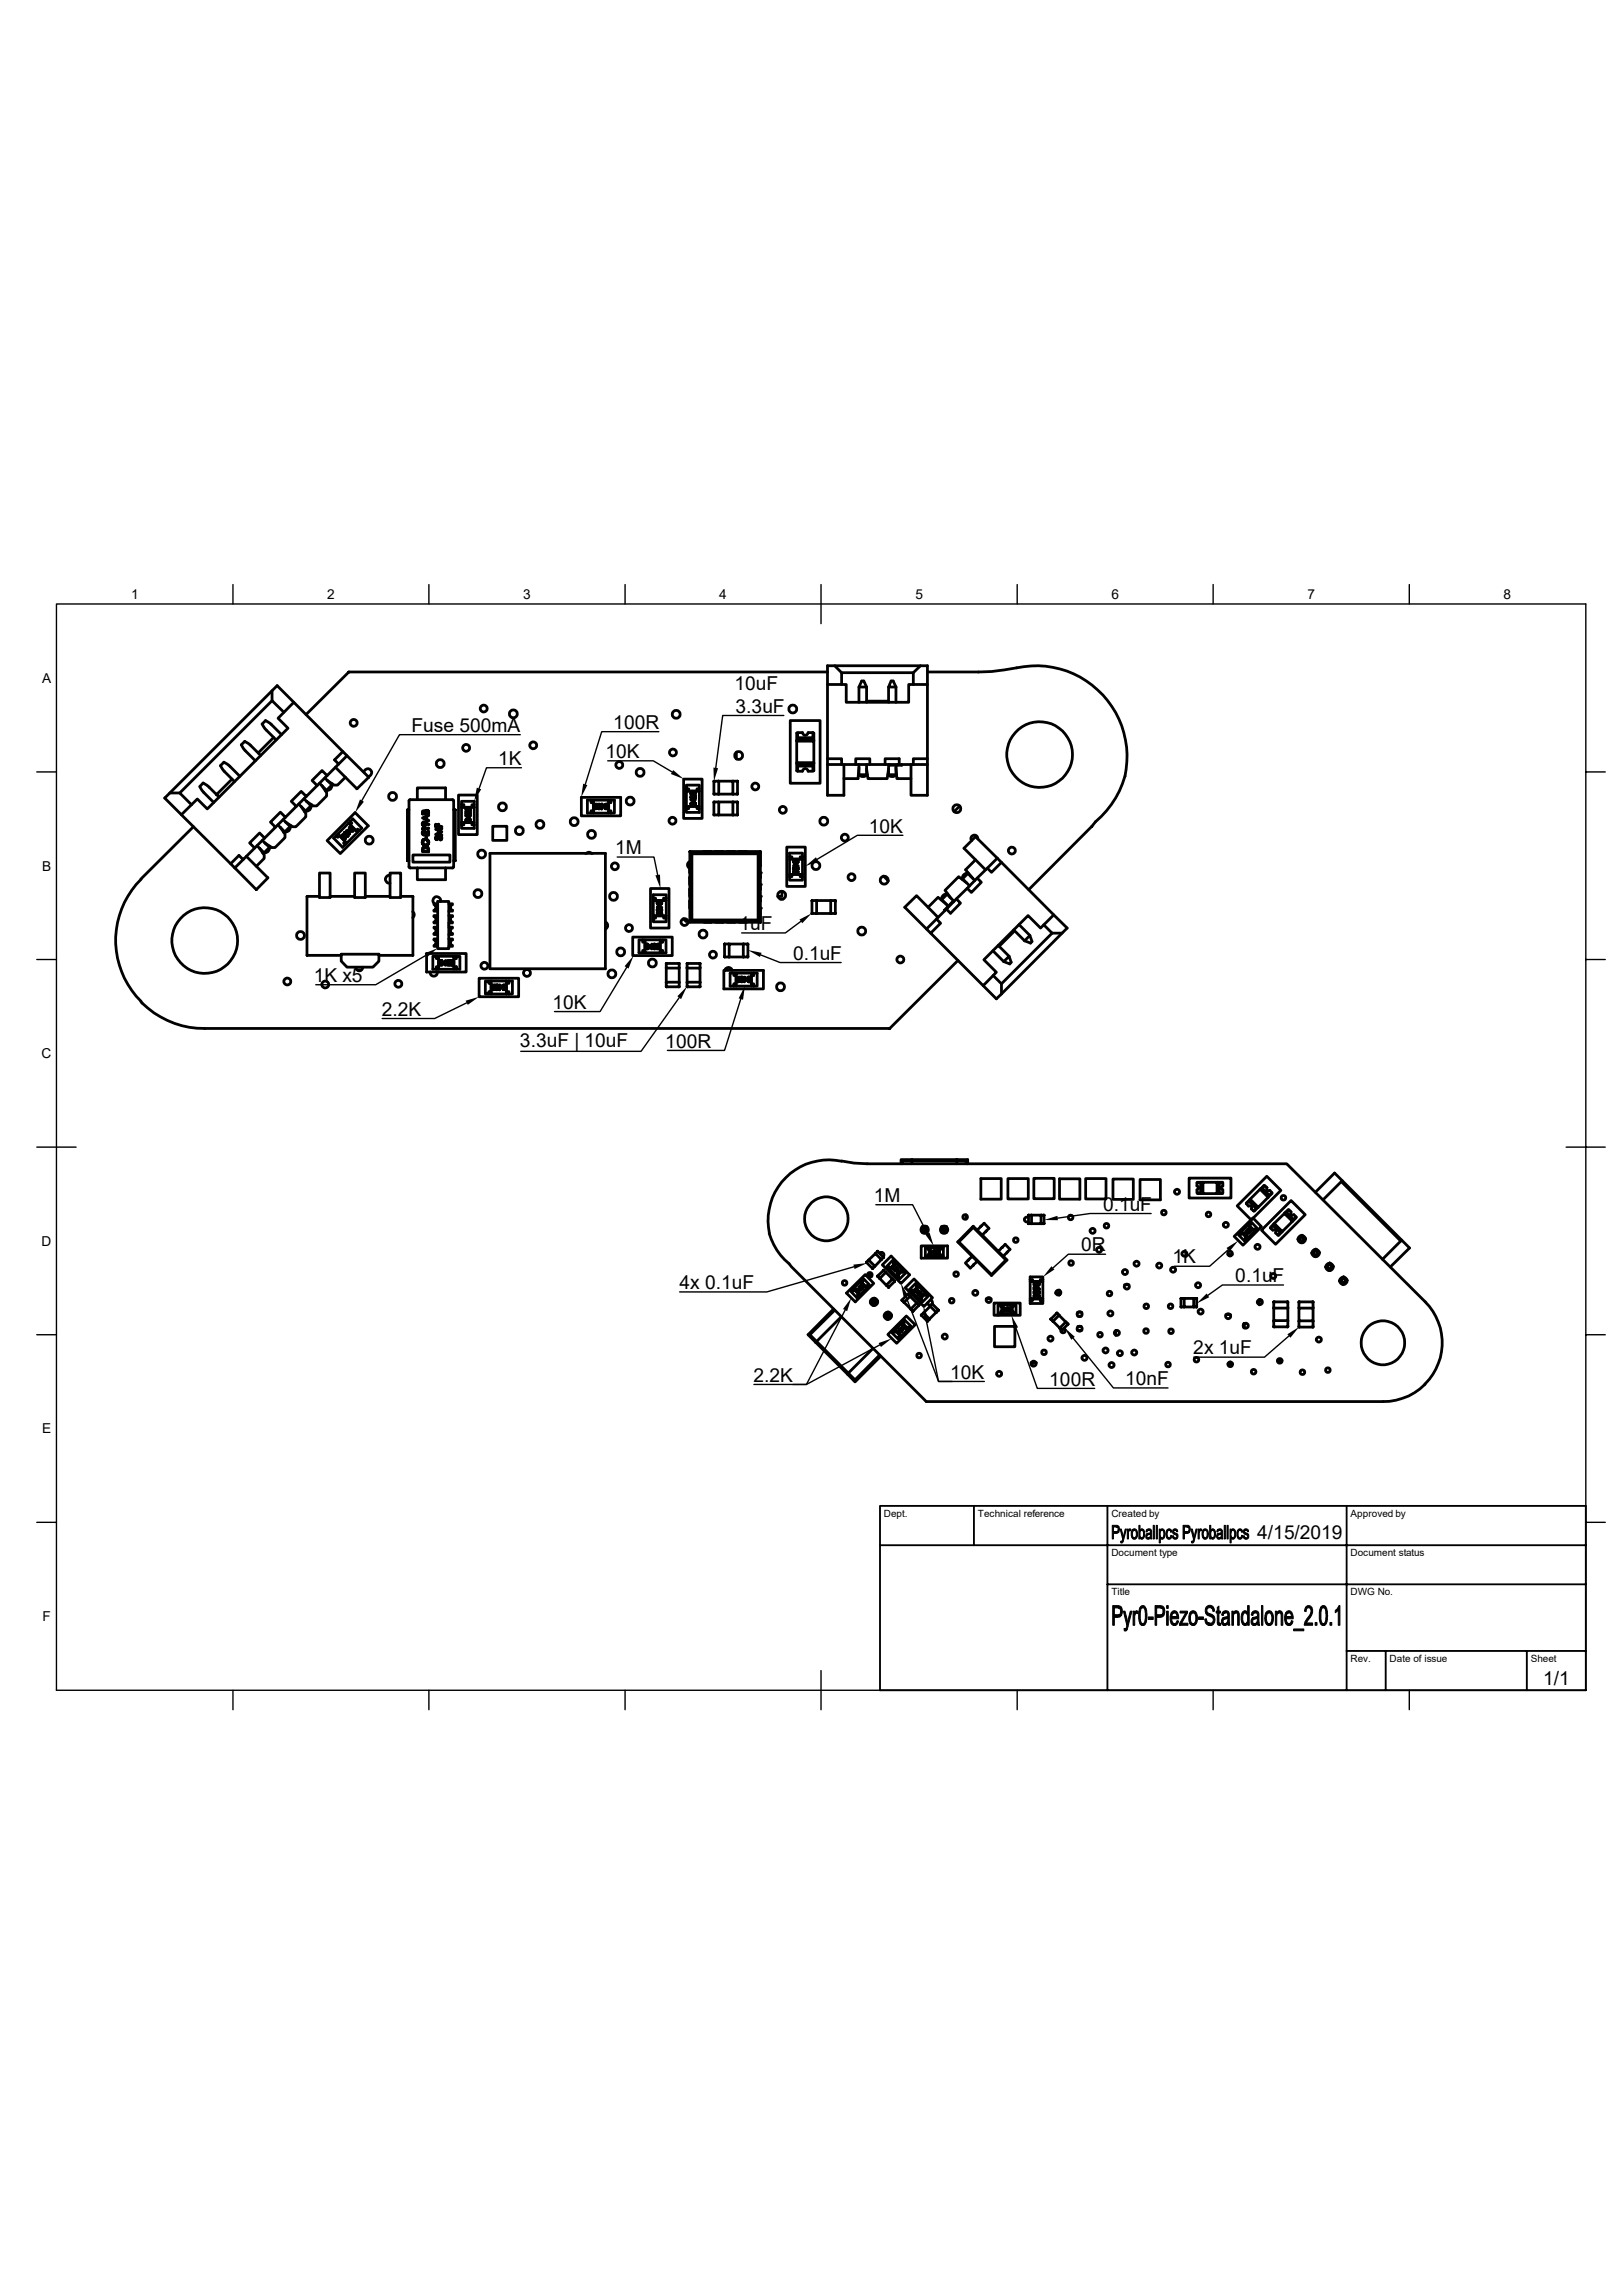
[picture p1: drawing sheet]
<svg xmlns="http://www.w3.org/2000/svg" width="297mm" height="420mm" viewBox="0 0 297 420" stroke-linecap="round" stroke-linejoin="round" font-family="sans-serif">
<defs><g id="words">
<g font-size="3.5">
<text x="134.4" y="126.2">10uF</text>
<text x="134.6" y="130.4">3.3uF</text>
<text x="75.3" y="133.9">Fuse 500mA</text>
<text x="112.2" y="133.4">100R</text>
<text x="91.1" y="140">1K</text>
<text x="110.8" y="138.8">10K</text>
<text x="159" y="152.4">10K</text>
<text x="112.6" y="156.3">1M</text>
<text x="135.3" y="170.2">1uF</text>
<text x="57.4" y="179.7">1K x5</text>
<text x="145.1" y="175.6">0.1uF</text>
<text x="69.9" y="185.9">2.2K</text>
<text x="101.1" y="184.7">10K</text>
<text x="95.1" y="191.6">3.3uF | 10uF</text>
<text x="121.8" y="191.7">100R</text>
<text x="159.9" y="220">1M</text>
<text x="201.8" y="221.6">0.1uF</text>
<text x="197.9" y="229">0R</text>
<text x="214.5" y="231.2">1K</text>
<text x="124.3" y="235.9">4x 0.1uF</text>
<text x="226.1" y="234.7">0.1uF</text>
<text x="218.4" y="247.9">2x 1uF</text>
<text x="137.9" y="252.9">2.2K</text>
<text x="173.9" y="252.3">10K</text>
<text x="192" y="253.6">100R</text>
<text x="205.9" y="253.5">10nF</text>
<text x="230.1" y="281.7">4/15/2019</text>
<text x="282.4" y="308.4">1/1</text>
</g>
<g font-size="2.5">
<text x="24" y="109.6">1</text>
<text x="59.9" y="109.6">2</text>
<text x="95.8" y="109.6">3</text>
<text x="131.6" y="109.6">4</text>
<text x="167.5" y="109.6">5</text>
<text x="203.4" y="109.6">6</text>
<text x="239.3" y="109.6">7</text>
<text x="275.1" y="109.6">8</text>
<text x="7.7" y="125">A</text>
<text x="7.7" y="159.3">B</text>
<text x="7.6" y="193.7">C</text>
<text x="7.6" y="228">D</text>
<text x="7.7" y="262.3">E</text>
<text x="7.8" y="296.6">F</text>
</g>
<g font-size="1.8">
<text x="161.8" y="277.6">Dept.</text>
<text x="178.9" y="277.6">Technical reference</text>
<text x="203.4" y="277.6">Created by</text>
<text x="247.1" y="277.6">Approved by</text>
<text x="203.4" y="284.8">Document type</text>
<text x="247.1" y="284.8">Document status</text>
<text x="203.4" y="292">Title</text>
<text x="247.1" y="292">DWG No.</text>
<text x="247.1" y="304.2">Rev.</text>
<text x="254.3" y="304.2">Date of issue</text>
<text x="280.1" y="304.2">Sheet</text>
</g>
</g></defs>
<g fill="none" stroke="#000" stroke-width=".51">
<path d="M47.7 138.3l-2.1-2.1-.8-.5-.6 .7 .5 .8 2 2M49.8 128.2l-16.9 16.9M49.8 126.4l-18.7 18.7M50.1 135l-2.9 2.8M51.5 134.5l-2.1-2.1-.8-.5-.6 .7 .5 .8 2 2M53.8 128.5l-3.1-3-.9 .9v1.8l2.1 2.1M62.7 137.5l.8 .8-1.5 1.5M63.5 138.3l4 3.9-2.2 2.2-3.9-4M134.7 137.7v1.2M144.6 131.9h5.5v11.4h-5.5zM145.8 139.6v.1h3.1M145.8 135.6h3.1v4"/>
<path d="M145.8 135.6v4h3.1M145.8 139.7v1.4h.2M146 134.2h-.2v1.3M146.8 134.1h-.8v.9h2.8v-.9h-.9M146.9 134.1a.51 .51 0 0 0 .5 .5 .51 .51 0 0 0 .5-.5M148.8 134.2h.1v1.4M148.9 135.5h-3.1v.1M148.9 139.6v1.5h-.1M151.4 138.9h2.6v1M151.4 125.3h3.5v3.2h11.4v-3.2h3.4v13.6h-2.6v1M151.4 139.9h18.3M151.4 123h-87.6l-7.8 7.8"/>
<path d="M152.7 121.8l1.3 1.3v2.2M154 123.1h13.1M156.6 139.9v-1h2.6v1M157.2 125.7v2.8M157.2 139.9v1.9h1.4v-1.9M157.7 124.6h.4l.5 1.1h-1.4zM158.6 125.7v2.8M158.6 128.3h4M162 139.9v-1h2.5v1M162.6 125.7v2.8M162.6 139.9v1.9h1.4v-1.8M162.8 139.9v.1h1.5"/>
<path d="M163.1 124.6h.3l.6 1.1h-1.4zM164 125.7v2.8M164.3 139.9v.1h.7v-.1M167.1 125.3v-2.2l1.3-1.3h1.3v3.5M168.4 121.8h-17v23.7h3v-5.6M169.7 123h9.4a50.8 50.8 0 0 0 8.3-1 16.5 16.5 0 0 1 18 21.4 17.1 17.1 0 0 1-5 7l-.6 .8-11.5 11.6M169.7 138.9v6.6h-3v-5.6M33.2 149.1l2.9-2.9 1.8 1.8 14.8-14.7-1.8-1.9 2.9-2.9 8.9 9-1.5 1.6 .8 .7-2.1 2.1-1-.9-1.8 1.8 .9 1-2 2-.9-1-1.8 1.8 .9 1-2 2-.9-1-1.8 1.9 .9 .9-2 2-.9-1-1.8 1.9 .9 .9-2.1 2.1-.8-.8-1.5 1.6M35.1 147.3l-2.2-2.2h-1.8l-1 1 12.9 12.7M35.4 151.3l-9.6 9.6M40.1 145.9l-2.1-2.1-.8-.5-.6 .6 .1 .3 .5 .7 1.9 2M42.5 142.6l-2.9 2.8"/>
<path d="M43.9 142.1l-2.1-2.1-.8-.5-.6 .7 .5 .8 2 2M44.5 157.3l-1.5 1.5M45.1 156.7l3.9 4-2.1 2.1-3.9-4M47 154.8l.5 .4M47.5 155.2l.8 1.3v.6l-1.4 1.4M48 153.8l.5 .5M48.4 153.4l-1.8 1.8M48.5 154.3l.8 .8-1 .9-.8-.8M49.4 154.9a1.08 1.08 0 0 1-1.3 1.2M51.3 151.4l.9 1.3v.6l-1.9 1.8h-.6l-1.2-.8M51.8 150l1.3 1.3-1 .9-1.3-1.2M52.2 149.6l-1.8 1.8"/>
<path d="M53.2 151a1.08 1.08 0 0 1-1.3 1.3M55.1 147.6l.9 1.3v.6l-1.9 1.8h-.5l-1.3-.8M55.6 146.2l1.3 1.2-1 1-1.2-1.2M56 145.8l-1.8 1.8M57 147.2a1.08 1.08 0 0 1-1.3 1.3M58.5 159.8h1.9v4.5h-1.9zM58.5 143.3l.4 .5M58.9 143.8l.9 1.3v.6l-1.8 1.8h-.7l-1.2-.9M59.4 142.4l.5 .4M59.9 153.8l5.1-5.1 2.4 2.4-5.1 5.1zM59.9 141.9l-1.9 1.9M59.9 142.8l.8 .9-1 1-.8-.9"/>
<path d="M60.8 143.4a1.08 1.08 0 0 1-1.3 1.3M61.8 152.6l2-2 1.6 1.7-1.9 2zM61.8 152.6l-.3 .3M62.8 152.7v.7l.1 .1 .3-.1v-.3a.28 .28 0 0 1 0 .4 .28 .28 0 0 1-.5-.1v-.6l-.3 .3zM63 152.4h.1a.45 .45 0 0 1 .6 .3v.3l-.3 .1-.5-.5zM63 152.5l.4-.1 .3 .3-.1 .3h-.2zM63.2 142.2l-1.4 1.5h-.7l-1.2-.9M63.4 152l.2 .1 .3-.2 .1 .8-.5-.4zM63.5 154.3l-.8 .8-1.7-1.7 .5-.5 .3 .3 .3-.3 1.1 1.1-.3 .3 .3 .3M63.6 152.2l.2-.2 .1 .4zM63.8 150.6l.8-.7 1.6 1.7-.8 .7M63.9 151.5l.2-.2 .3 .1 .3 .4-.1 .3h-.4l-.3-.3z"/>
<path d="M64 151.5h.3l.3 .3v.2h-.3l-.3-.2zM64.1 150.3l.3 .3-.3 .4 1.1 1 .2-.3 .3 .3M64.9 159.8h1.9v4.5h-1.9zM66.6 141.3a.72 .72 0 0 1 .7-.6 .72 .72 0 0 1 .7 .7 .72 .72 0 0 1-.6 .7M71.4 159.8h1.9v4.5h-1.9zM74.8 148.2h-.3v9.3h.3M74.9 146.4h8.1v12.4h-8.1zM75.6 156.5h6.7v1.3h-6.7zM76.4 146.3v-2.1h5.1v2.1M76.4 158.8v2.2h5.1v-2.2M77.3 149.7l1.1-.6v.2l-.3 .1v.5l.3 .2v.1zM77.3 150.6l.2-.2h.3l.7 .5-.1 .1-.5-.3v.3a.37 .37 0 0 1-.5 0 .37 .37 0 0 1-.1-.4z"/>
<path d="M77.3 151.6h1.1h-1v.3zM77.3 152.3l.5-.2 .5 .6v-.6h.1v.8l-.4-.5a.28 .28 0 0 0-.4-.2 .28 .28 0 0 0-.1 .5l.1 .1a.36 .36 0 0 1-.3-.1 .36 .36 0 0 1 0-.4zM77.3 148.5l.4-.1 .1 .1 .2-.2h.2l.2 .2v.5h-1.1zM77.3 155.2l.3-.2a.63 .63 0 0 1 .8 .3v.6h-1.1zM77.4 150.6a.26 .26 0 0 1 .4 0 .26 .26 0 0 1-.1 .4l-.3-.1zM77.5 148.5l.3 .1v.2h-.4zM77.5 149.7l.4-.2v.4zM77.5 155.2l.2-.2 .4 .1 .2 .2v.4h-.9zM77.9 153h.2v.4h-.2zM77.9 148.5h.4v.3h-.4zM79.7 150.8l.1 .5h.4v-.5h.1v.5h.6v.1h-1.2zM79.7 151.8l1.2-.2v.1l-.9 .1 .9 .4-.9 .5 .9 .2-1.2-.2 .9-.5z"/>
<path d="M79.8 153.1l.1 .1-.1 .1v.2l.3-.1a.43 .43 0 0 1 .7-.2l.1 .3-.3 .2 .2-.3-.2-.2h-.1l-.6 .5-.2-.2zM83 148.2h.3v9.3h-.3M83.9 145.5h3.4v7.2h-3.4zM84.5 146.6h2.3v.7h-.4v.4h-1.5v-.4h-.4zM84.5 151h.4v-.5h1.5v.5h.4M84.5 147.3v3.7M84.5 147.7h2.3M85.2 148.6l.2-.1h.5l.2 .4-.2 .2h-.5l-.2-.2zM85.2 148l.4-.2 .4 .4v-.4h.1v.6l-.5-.5-.3 .1 .2 .4-.2-.1zM85.2 149.2l.7-.1 .2 .2h-.2v.4zM85.3 148.7l.5-.2 .2 .1v.2l-.1 .2h-.5zM85.3 149.9h.7l.1 .3-.2 .1a.38 .38 0 0 1-.5 .1 .38 .38 0 0 1-.1-.5z"/>
<path d="M85.3 149.9h.6l.1 .3-.2 .1h-.3l-.2-.1zM85.4 149.3h.4v.3zM86.8 147.7v2.8h-2.3M86.8 150.5v1.1h-2.3v-.6M86.8 147.3v.4M89.7 156.2h21.1v21.1h-21.1zM90.2 151.2h2.6v2.6h-2.6zM106.4 145.9h7.2v3.4h-7.2zM107.2 156.2a.72 .72 0 0 1 1.1 0M108.2 146.4v.5h.4v1.5h-.4v.4h-.7v-2.4h1.1M108.2 148.8h.4M108.6 146.4h2.8v2.4h-2.8z"/>
<path d="M108.7 147.2h.6l-.5 .5 .1 .3 .3-.3-.1 .3h-.4v-.3l.4-.5zM109.4 147.2h.3l.2 .1v.6l-.2 .1h-.2l-.2-.2zM109.5 147.3h.3l.1 .4-.2 .3-.3-.2zM110.1 147.2l.1 .2h.4l-.5 .6v-.6h-.1zM110.1 148h.1M110.2 147.4h.2l-.2 .4zM110.7 147.2h.4l.2 .2v.4l-.2 .2h-.3l-.1-.1zM110.8 147.3l.2-.1 .2 .2-.2 .6-.3-.2zM111.4 146.4h1v2.4h-.6M111.4 148.8h.4M111.8 146.4v.5h-.4v1.5h.4v.4M125.1 142.6h3.4v7.2h-3.4z"/>
<path d="M125.6 143.7h2.4v.7h-.4v.4h-1.6v-.4h-.4zM125.6 148h.4v-.4h1.6v.4h.4M125.6 144.4v.4M125.6 147.6v.4M126.2 155.9h12.9l-.4 .4h-12.1zM126.2 158.5v1.2M126.2 157.6a.68 .68 0 0 0-.4 .7 .68 .68 0 0 0 .4 .6M126.4 146.3l.7-.1 .2 .2h-.2v.4zM126.4 145l.4-.1 .4 .4 .1-.4v.6l-.6-.6-.2 .1 .2 .4h-.2zM126.4 147l.6-.1 .3 .1v.2l-.3 .2h-.3h-.3zM126.4 145.6l.7-.1 .2 .3a.5 .5 0 0 1-.9 .2zM126.5 147.1l.5-.2 .2 .3-.2 .2h-.4z"/>
<path d="M126.5 145.7l.5-.1 .2 .3-.1 .1-.4 .1-.2-.2zM126.6 146.4h.4v.2zM126.6 156.3v12.1M128 144.8v2.8h-2.4M128 144.8h-2.4v2.8M128 147.6v1.1h-2.4v-.7M128 144.4v.4M128.8 155.9h1.3M130.7 149.1h.1M130.7 145.2v.1M130.7 146.8v.1M130.7 143h.1"/>
<path d="M130.9 155.9h1.3M131.4 146.8l.1 .1M131.4 143h.1M131.5 149.1h-.1M131.5 145.2l-.1 .1M131.5 143h2.6v2.3h-2.6M131.5 146.8h-.9v2.3h4.4v-2.3h-.9M131.5 143h-.9v2.3h.9M131.5 143v2.3M133.1 155.9h1.3M134.1 146.8h-2.6v2.3M134.1 146.8v2.3"/>
<path d="M134.1 143h.9v2.3h-.9M134.1 149.1h.1M134.1 145.2l.1 .1M134.2 146.8l-.1 .1M134.2 143h-.1M134.9 146.8l.1 .1M134.9 143h.1M135 149.1h-.1M135 145.2l-.1 .1M135.3 155.9h1.3M139.1 155.9h-12.9v12.9h12.9M139.1 155.9v12.9l-.4-.4v-12.1"/>
<path d="M139.1 159.7l.1 .9M139.1 155.9l.1 2.6M144 155h3.4v7.2h-3.4zM144.5 157.2h2.4v2.8h-2.4zM144.5 156.8h.4v.4h1.5v-.4h.5M145.2 157.5l.6-.1 .2 .1 .1 .2-.3 .2h-.3l-.3-.1zM145.2 159.3l.3 .4a.21 .21 0 0 0 .2 .2 .21 .21 0 0 0 .3-.2 .21 .21 0 0 0-.2-.2l.1-.1 .2 .2-.1 .3h-.4l-.3-.4-.1 .4zM145.2 158.8l.6-.1a.3 .3 0 0 1 .3 .2 .3 .3 0 0 1-.3 .4l-.5-.1-.1-.2zM145.3 158.9l.5-.1 .2 .2-.2 .2h-.4zM145.3 157.5l.5-.1 .2 .2-.1 .2a.38 .38 0 0 1-.6-.3zM145.4 158l.7 .5h-.9l.2-.1zM145.5 158.2l.4 .2h-.4z"/>
<path d="M146.8 141.1h-.8v-.9h2.8v.9h-.9M146.9 141.1a.51 .51 0 0 1 .5-.5 .51 .51 0 0 1 .5 .5M146.9 156.8v-.7h-2.4v1.1M146.9 156.8v.4M157.2 140.5l-.2 2h-2.6M158.6 140.7l.2 1.8h3.5l.3-1.8M158.7 141.7a1.03 1.03 0 0 1-1.6 .1M162.5 141.7a1.03 1.03 0 0 0 1.6 .1M164 140.5l.1 2h2.6M175.6 147.5l-1 1M177.2 159.8a1.06 1.06 0 0 0-1.1 1.1M178.5 157.4l-1.8 1.8 1.4 1.6"/>
<path d="M178.9 153.5a.64 .64 0 0 0-.7-.7 .64 .64 0 0 0-.4 1M182.5 157.1l12.8 12.7-12 12.1M182.5 157.1l-11.1 11.1M182.5 157.1l-4-4-2.1 2.1 3.9 4M183.3 157.8l-1.9 1.8-.7-.7M25.8 160.9a15.7 15.7 0 0 0 0 22.4M58.5 164l-2.3 .1v10.7h6.2M60.4 164h4.5M62.4 174.6h6.9v1.3l-1.1 1.1h-4.7l-1.1-1.1zM65.1 177a.64 .64 0 0 0 .6 .7 .64 .64 0 0 0 .7-.7M66.8 164h4.6M71.4 160.2a.73 .73 0 0 0-.9 .7 .73 .73 0 0 0 .9 .7"/>
<path d="M73.3 164l2.3 .1v10.7h-6.3M75.5 166.8a.66 .66 0 0 1 0 1.1M78.1 174.5h7.2v3.4h-7.2zM78.7 177.9a.65 .65 0 0 0 .7 .7 .65 .65 0 0 0 .6-.7M79.8 175v.4h.5v1.5h-.5v.5M79.8 175h-.6v2.4h1.1M79.8 175h.5M80.1 167.6h-.7v.1l.4 .2v.7l-.4 .1v.2h.7M80.1 165.4h-.7v.2l.4 .1v.7l-.4 .2v.2h.7M80.1 169.7h-.7v.1l.4 .2v.7l-.4 .2v.1h.7M80.1 171.8h-.7v.2l.4 .2v.6l-.4 .2v.2h.7M80.1 165h2v8.6h-2z"/>
<path d="M80.3 175h2.8v2.4h-2.8zM80.5 175.9l.3-.1 .2 .2v.4l-.2 .3-.4-.2zM80.5 175.9h.3l.1 .1v.4l-.1 .2-.3-.1zM80.6 165a.71 .71 0 0 0-.9-.9 .71 .71 0 0 0-.2 1.3M81.5 176v.4h-.3zM81.5 175.8v.6h.2h-.2v.3v-.3h-.4zM81.8 175.8h.3l.2 .1v.6l-.2 .2-.4-.2zM81.9 175.9a.32 .32 0 0 1 .4 .3 .32 .32 0 0 1-.4 .3zM82.1 165.4h.7v.2l-.3 .1v.7l.3 .2v.2h-.7M82.1 167.6h.7v.1l-.3 .2v.7l.3 .1v.2h-.7M82.1 171.8h.7v.2l-.3 .2v.6l.3 .2v.2h-.7M82.1 169.7h.7v.1l-.3 .2v.7l.3 .2v.1h-.7"/>
<path d="M82.5 175.8h.3l.2 .1-.1 .3-.3 .4 .4 .1h-.6l.5-.6-.1-.2h-.2l-.2 .2zM83.1 175.4h.4v-.4h.7v2.4h-.7v-.5h-.4zM83.1 177.4h.4M83.1 175h.4M87.7 179h7.2v3.4h-7.2zM88.8 179.5h.7v.5h.4v1.5h-.4v.4h-.7zM89.5 179.5h4.3v2.4h-.7M89.9 179.5v2.4h2.8M92.7 179.5v2.4M93.1 179.5v.5h-.4v1.5h.4v.4M110.8 168.7a.75 .75 0 0 1 .4 .7 .75 .75 0 0 1-.4 .7M115.8 171.5h7.2v3.4h-7.2z"/>
<path d="M117.6 172v.4h.4v1.5h-.4v.5M117.6 172h-.7v2.4h1.1M117.6 172h.4M118 172h2.8v2.4h-2.8zM118.2 172.9a.35 .35 0 0 1 .5 0 .35 .35 0 0 1 0 .5l-.1 .3-.4-.1zM118.2 173l.2-.2 .2 .1 .1 .5-.2 .2-.3-.2zM119 162.6h3.4v7.2h-3.4zM119.2 173v.4h-.2zM119.3 172.8l.1 .6-.2 .3v-.3h-.4zM119.5 164.8h2.4v2.8h-2.4zM119.5 168h.5v-.4h1.5v.4h.4v.7h-2.4zM119.5 172.8h.3l.2 .1a.47 .47 0 0 1-.4 .8l-.1-.3z"/>
<path d="M119.5 164.4h.5v.4h1.5v-.4h.4M119.5 167.6v.4M119.6 172.9l.2-.1a.36 .36 0 0 1 .1 .6l-.1 .2a.38 .38 0 0 1-.3-.3 .38 .38 0 0 1 .1-.4zM120.1 173.7l.4-.4-.2 .3h.4zM120.2 166.5l.6-.3 .3 .2v.3l-.2 .1h-.5zM120.2 172.8h.4a.29 .29 0 0 1-.1 .5l.1-.4-.2-.1-.2 .3zM120.3 166.9l.3 .4a.24 .24 0 0 0 .4 .1 .24 .24 0 0 0-.1-.4l.2 .1-.1 .4h-.3l-.3-.4-.1 .4zM120.3 165.1l.2-.2a.37 .37 0 0 1 .6 .2v.3l-.1 .1h-.5l-.3-.2zM120.4 166.4h.5l.1 .3-.5 .1-.2-.2zM120.4 165.1l.5-.1 .1 .3-.5 .1-.2-.1zM120.4 165.6l.7 .5h-.6l-.1 .1v-.1h-.1l.1-.1zM120.5 165.7l.4 .3h-.4z"/>
<path d="M120.8 174.4h1.1v-2.4h-.7v.4h-.4v1.5h.4v.5M120.8 172h.4M121.9 177.2h2.4v2.5h-2.4M121.9 164.4v-.7h-2.4v1.1M121.9 164.4v.4M121.9 167.6v.4M122 177.1h.1M122 176.3v.1M122 179.8h.1M124.2 179.8h.1M124.2 176.3v.1M124.2 177.1h.1"/>
<path d="M124.3 177.2v-.9h-2.4v4.3h2.4v-.9M125.1 168.1l.5 .6 .2-.3M125.7 177.2h2.4v2.5M125.7 177.2v2.5h2.4M125.7 179.7v.9h2.4v-.9M125.7 177.2v-.9h2.4v.9M125.8 177.1h.1M125.8 179.8h.1M125.8 176.3v.1M126.2 164.9v1.3M126.2 162.7v1.3M126.2 160.6v1.3"/>
<path d="M128.1 179.8h.1M128.1 176.3v.1M128.1 177.1h.1M128.8 168.8h1.3M130.9 168.8h1.4M132.5 177.6h7.2v3.4h-7.2zM132.6 175v.1M132.6 177.6a.69 .69 0 0 1 .7-.6 .69 .69 0 0 1 .7 .6M132.6 172.8h.1M133.1 168.8h1.4M133.3 172.8h.1M133.4 175l-.1 .1"/>
<path d="M133.4 172.8h-.8v2.3h4.3v-2.3h-.9M134.3 178.1v.4h.4v1.5h-.4v.5h-.7v-2.4h1.1M134.7 178.1h2.8v2.4h-2.8zM134.8 178.8h.6l-.5 .5v.2l.3 .1 .1-.2a.24 .24 0 0 1-.3 .3 .24 .24 0 0 1-.2-.4l.4-.4zM135.3 168.8h1.3M135.5 178.9h.1a.4 .4 0 0 1 .5 .1 .4 .4 0 0 1-.1 .5l-.2 .2-.3-.1zM135.6 178.9h.2l.1 .1 .1 .4-.2 .2-.2-.1zM136 172.8h-2.6v2.3M136 172.8v2.3M136.1 175v.1M136.1 172.8h.1M136.2 178.8l.1 .2h.4l-.5 .7v-.6h-.1z"/>
<path d="M136.3 179.1h.3l-.3 .4zM136.8 172.8h.1M136.9 178.9l.1-.1a.48 .48 0 0 1 .4 .4 .48 .48 0 0 1-.3 .5l-.3-.3zM136.9 175l-.1 .1M136.9 178.9h.3v.7l-.3-.1zM137.5 178.1h1.1v2.4h-.7M137.9 178.1v.4h-.4v1.5h.4v.5M138.7 168.4h-12.1l-.4 .4M139.1 164l.1 .9M139.1 161.9l.1 .8M139.1 168.8h.1M139.1 166.2v2.6"/>
<path d="M142.8 164.6h.5M143.1 163.1v.9h-.8M144.5 160.4h.4v-.4h1.5v.4h.5v.7h-2.4zM144.5 160v.4M146.9 160v.4M148.6 167.1v.1M148.6 164.8v.1M149.4 164.8v.1M149.4 167.1v.1M149.4 164.8h2.6v2.4h-2.6zM149.4 164.8h-.8v2.4h.8M152 167.2h.9"/>
<path d="M152 164.8h.9v2.4M152.1 167.1v.1M152.1 164.8v.1M152.8 164.8l.1 .1M152.9 167.1l-.1 .1M161.7 160.3l.9 .9M171.4 168.2l-1.9 1.8M171.7 167.9l-4-4-2.1 2.1 4.7 4.8M173.3 165.6l-1.6-1.4-1.9 1.8M173.4 163.6a1.04 1.04 0 0 0-1.1 1.1M173.4 166.1v-.1l-.6 .6 .1 .1M174.5 165.1l-.1-.1-1 1"/>
<path d="M174.6 164.9l-1.3-1.2-1 .9 1.2 1.2M175 164.5l.8 .8-1.9 1.8-.7-.7M175.3 175.8l-12.5 12.4h-125.4M176.9 161.5l-1.5-1.1-2.5 2.5 1.1 1.5M178.4 161.2l-1.3-1.3-1 .9 1.3 1.3M178.8 160.7l.8 .8-1.8 1.8-.8-.7M181.7 174l2 2M181.7 178.5l1.6 1.5v1.9l-1 .9-2.4-2.4M182.7 173l2 2M183.7 176l1-1 .3 1.1-.2 .3zM185.5 170.2l2 2M185.7 170.3l-2.9 2.9"/>
<path d="M186.5 169.2l2 2M187.5 172.2l1-1 .3 1.1-.2 .3zM191 169.2l1.5 1.6h1.9M192.5 170.8l-9.2 9.2M192.8 167.4l-2.4 2.4-2.3-2.2-8.1 8 2.3 2.3-2.4 2.5-9.6-9.6 1.8-1.8-.7-.8M25.8 183.3a16.1 16.1 0 0 0 11.7 4.9M89.5 181.9h.4M90 180.3h.6l-.5 .5v.2l.2 .1 .3-.3a.3 .3 0 0 1-.3 .3 .3 .3 0 0 1-.4-.2 .3 .3 0 0 1 .3-.3l.2-.3zM90.7 180.3h.4l.1 .5a.28 .28 0 0 1-.2 .3 .28 .28 0 0 1-.3-.3zM90.8 180.4l.2-.1 .1 .2v.5h-.3l-.1-.2zM91.4 180.3l.1 .1h.4l-.5 .7-.1-.5zM91.5 180.6h.2l-.2 .3z"/>
<path d="M92.1 180.4l.1-.1 .3 .1-.1 .6-.3-.1zM92.1 180.3l.2-.1 .2 .1v.6a.28 .28 0 0 1-.2 .2 .28 .28 0 0 1-.3-.2zM92.7 181.9h.4M122 180.6h.1M124.2 180.6h.1M125.8 180.6h.1M128.1 180.6h.1M134.3 180.5h.4M137.5 180.5h.4M154 212.5l2.3 .4 2.4 .1h76.8l25.3 25.3a10.7 10.7 0 0 1 2.2 11.7 10.7 10.7 0 0 1-9.9 6.5h-83.6l-25.1-25.2a11.1 11.1 0 0 1-3.6-5.6M154 212.5a11.1 11.1 0 0 0-13.2 13.2M165.2 213v-.5h11.6v.5"/>
<path d="M166.9 212.2h-2v.8M166.9 212.2v.8M166.9 212.2h10.2v.8M175.1 212.2v.8M179.5 215.7h3.7v3.8h-3.7zM184.4 215.7h3.8v3.7h-3.8zM189.2 215.6h3.7v3.8h-3.7zM193.9 215.7h3.7v3.8h-3.7zM198.7 215.7h3.7v3.7h-3.7zM203.7 215.8h3.7v3.7h-3.7zM208.6 215.9h3.7v3.7h-3.7zM217.6 215.6h7.7v3.6h-7.7z"/>
<path d="M219 217.7l.4-.2-.2-.4-.2-.1v-.5h.7v1.8h-.7v-.5M219.1 218.3v.1h.9M220 216.4l-.9 .1M220.1 216.4h2.6v2h-2.6zM220.1 216.4h-.1v2h.1M222.7 216.4h.1M222.8 216.4v2h-.1M222.8 216.4l.9 .1M223.7 218.3v.1h-.9M223.8 217.7l-.4-.2 .2-.4 .2-.1v-.5h-.7v1.8h.7v-.5M228.7 219.6l-.7 .6 .1 .1M228.8 219.5l-.1 .1 1.4 1.4"/>
<path d="M230.6 217.6l-1.8 1.9 1.5 1.4 1.8-1.8M230.6 217.6l1.5 1.5M230.7 217.6l1.5 1.4-.1 .1M230.7 217.6h-.1M231 217.4l.4-.4 .5 .3-.1 .5 .4 .1 .2-.1 .3 .5-.4 .4zM231.4 217l-.1-.1-.6 .7M231.8 215.3l2.6 2.5-5.4 5.5-2.6-2.6zM232.7 218.3l.1 .1-.6 .6M236.3 219.7l2.5 2.6-5.4 5.4-2.6-2.6zM240.7 218.2l3.5-3.5 13.7 13.7-3.5 3.5M245.4 216.2l10.9 10.9M245.6 216.1l-3.5 3.5"/>
<path d="M152.5 239.6l-4.6 4.7 1.4 1.4M152.7 239.8l-4.5 4.5 8.3 8.2 4.5-4.5M154.9 236.6l3.4-3.3 1.6 1.6-3.4 3.4zM156 236.1l.2 .2 .2-.2 .7 .7-.2 .2 .2 .2M156 236.1l-.3 .2 1.1 1.2 .5-.5M156.2 235.8l1.3-1.3 1.1 1.2-1.3 1.3zM156.2 235.8l-.2 .3M156.7 236.1l.2-.1 .2 .1 .1 .4h-.3l-.2-.2zM156.8 236.1h.3v.3l-.3-.1zM157.1 235.6l.5 .5-.2-.1-.1 .2zM157.2 235.8l.2 .1-.1 .2zM157.3 235.5a.36 .36 0 0 1 .6 .1 .26 .26 0 0 1-.3 .2 .26 .26 0 0 1-.2-.2z"/>
<path d="M157.4 235.5l.2-.1 .2 .4h-.2zM157.6 235.1l.3-.1 .1 .5 .2-.1-.3 .2v-.5h-.1l-.1 .2zM157.7 234.3l.3-.3 1.1 1.2-.3 .3-.2-.3-.2 .3-.7-.8 .2-.2zM157.7 234.3l-.2 .2M158.7 233.3l.3-.2 .5 .5M158.8 235.5l-.2 .2M158.9 233.6l.2-.3 .3 .3M158.9 230.6h.1M159 230.6l1.2-1.2 1.1 1.1-1.2 1.2zM159 230.6l-.4 .5 1 1 .5-.4M159.3 238.3l.6 .6M159.7 238.3l.2 .2"/>
<path d="M160 237.6l-.7 .7h.4l.3-.3M160.1 231.7v.1M160.1 238.2h.5l-.7 .7v-.4zM160.1 238.2l-.1-.2v-.4l.6 .6M160.2 229.4l.4-.4 1.1 1.1-.4 .4M160.6 229h.1M160.6 233.5l.4 .5M160.6 233.5v.1M161 229.3a.48 .48 0 0 1 .6 0 .48 .48 0 0 1 0 .7M161 233.9h.1M161.2 230.5h.1M161.5 231.5l1.6-1.6 3.4 3.4-1.6 1.6z"/>
<path d="M161.6 232.5h.1M161.7 230v.1M162.1 232.8v.1M162.1 232.8l1.2 1.3-1.1 1.1-1.2-1.2zM162.1 232.8l-.4-.3-1.1 1M162.2 235.2h.1M162.6 235.6h.1M162.6 232.1l.2 .2M163.3 234.1h.1M163.3 234.1l.4 .4-1.1 1.1-.4-.4M163.4 230.6l.3 .4-.3 .1 .3 .3-.8 .7-.1-.2-.2 .2-.3-.3zM163.5 231.6l.4 .2-.6 .1v.2h.3l-.2 .1-.2-.2 .1-.2h.4z"/>
<path d="M163.6 232.2l.2-.3 .3 .1-.3 .5-.2-.1zM163.6 232.2l.4-.2a.21 .21 0 0 1-.1 .3 .21 .21 0 0 1-.3-.1zM163.7 231l.2 .1M163.9 231.1l-1.1 1.2 1.3 1.3M163.9 231.1l1.3 1.4M164 232.6l.2-.2 .1 .1zM164.1 232.3l.2-.1 .1 .3-.6 .1zM164.1 233.6l.2 .2M164.3 232.8l.2-.2 .1 .1v.1l-.2 .2zM164.3 232.7a.24 .24 0 0 1 .4 0 .24 .24 0 0 1-.2 .3h-.3zM165.1 238l.3 .3M165.2 232.5l-1.1 1.1"/>
<path d="M165.2 232.5l.2 .2M165.4 232.7l-.2 .2-.2-.2-.7 .7 .2 .2-.2 .2M165.4 232.7l.3 .3-1.1 1.1-.3-.3M165.4 238.3h.1M165.4 238.3l1.1-1.1 1.3 1.3-1.1 1.1zM166.1 236.9h.1M166.5 237.3l-.3-.5-1.1 1.2M167 236.5l1.1-1.1 1.3 1.3-1.1 1.1zM167 239.9h.1M167.3 234.1l3.3 3.4-1.5 1.6-3.4-3.4zM167.5 236.1l.1-.1a.16 .16 0 0 1 .2 .1 .16 .16 0 0 1-.1 .2h-.2zM167.6 236h.3l-.2 .4-.3-.1z"/>
<path d="M167.7 238.5l.5 .3-1.2 1.2-.3-.5M167.8 236.4l.5-.1-.4 .4zM167.9 236.4h.2l-.1 .2zM167.9 235.2l-.3 .2 .3 .1-.8 .8-.1-.2-.2 .2M167.9 235.2l-.3-.3-1.1 1.1 .5 .5M167.9 235.2l.2 .2M168.1 238.8v.1M168.2 236.6l.2-.1 .2 .1-.3 .4-.2-.1zM168.2 236.6h.3l-.1 .3h-.3zM168.3 237.8l.2 .2M168.5 237.6l.7-.7 .2 .2 .2-.2 .3 .3-1.1 1.1-.3-.3 .2-.2zM168.6 236.9l.2-.1 .1 .1-.1 .3h-.4l.2 .2-.3-.2 .5-.1v-.2z"/>
<path d="M168.6 228h4.8v2.3h-4.8zM168.7 224.5l.3 .3v.4l-.3 .3zM168.7 224.5h.9M169 225.2h.3l.3 .3h-.9M169 224.8h.3M169.3 225.2v-.4l.3-.3v1M169.4 236.7l.2 .2M169.8 228.3v.3h.3v1h-.3v.3M170.1 228.3v1.6h1.8M170.2 228.9h.2l.1 .1-.1 .4a.3 .3 0 0 1-.3-.1 .3 .3 0 0 1 .1-.4zM170.2 239.1l1.1 1.1-1.2 1.2-1.1-1.1zM170.2 228.9l.3 .1-.1 .4-.2-.1z"/>
<path d="M170.2 239.1l.4-.5 1.1 1.2-.4 .4M170.3 237.9a.47 .47 0 0 1 .2 .8 .47 .47 0 0 1-.8-.2M170.6 238.7h.1M170.9 229v.2h-.2zM170.9 228.9l.1 .4-.1 .1v-.1h-.3zM171.1 228.9h.2l.1 .1-.1 .4a.3 .3 0 0 1-.3-.1 .3 .3 0 0 1 .1-.4zM171.1 228.9h.2v.5l-.2-.1zM171.5 228.9h.3l-.2 .5h.2h-.4l.4-.3v-.2zM171.7 239.7v.1M171.9 228.6h.3v-.3h.4v1.6h-.4v-.3h-.3zM171.9 228.3v1.6M171.9 229.9h.3"/>
<path d="M172.2 228.3h-2.9v1.6h.8M172.3 224.5l.3 .3v.4l-.3 .3zM172.3 224.5h.9M172.6 225.2h.3l.3 .3h-.9M172.6 224.8h.3M172.9 225.2v-.4l.3-.3v1M175.3 227.3l6.1 6.1M176.8 222.3v.8M177.9 229.9l-1.2 1.2 .8 1 1.3-1.3M178.1 224.4l6.2 6.2M178.1 224.6l-2.6 2.7 5.9 6M178.1 224.6v-.2l-2.8 2.9h.2"/>
<path d="M178.1 224.6l6 6M178.8 225.1l1.3-1.2 .9 .9-1.3 1.2M180.5 237.7h.9M181.9 238.5h4.8v2.2h-4.8zM182.7 229l1.2-1.3 .9 .9-1.2 1.3M183.1 238.8v.3h.2v1h-.2v.3M183.1 238.8h-.5v1.6h.7M183.1 238.8h.2M183.3 238.8h1.9v1.6h-1.9zM183.5 239.4h.3l-.1 .5-.2-.1zM183.6 239.4h.2l-.1 .5-.2-.1zM184.1 230.6h.2l-2.9 2.8v-.1z"/>
<path d="M184.1 239.4v.3h-.1zM184.2 239.3v.6l-.3-.1zM184.4 239.4h.3l-.1 .5-.2-.1zM184.8 239.4l.1-.1 .2 .1 .1 .1-.3 .3 .3 .1h-.4l.3-.4-.1-.1zM185.2 238.8h.3M185.5 238.8h.4v1.6h-.4v-.3h-.3v-1h.3zM188.2 222.8a.47 .47 0 0 0-.8 .4 .47 .47 0 0 0 .8 .4M188.2 223.9h.1M188.3 222.4h-.1M188.5 234.5h2.3v3.2h-2.3zM188.5 238h.4v-.3h1.5v.3h.4v.5h-2.3zM188.5 234.2h.4v.3h1.5v-.3h.4"/>
<path d="M188.5 237.7v.3M188.7 222.4h.1M188.8 222.4h1.7v1.5h-1.7zM188.8 222.4h-.6v1.5h.6M188.8 223.9h-.1M189.2 236.4l.3-.2h.4l.3 .1v.3l-.3 .3h-.4l-.3-.3zM189.2 235.6l.2-.1h.2l.6 .4-.4-.2v.2l-.4 .2-.2-.1zM189.2 234.8l.5-.2 .3 .1 .2 .2a.55 .55 0 0 1-.3 .4 .55 .55 0 0 1-.6-.1l-.1-.1zM189.3 236.4l.2-.1h.5l.1 .3-.6 .2-.2-.2zM189.3 235.6a.21 .21 0 0 1 .3 0 .21 .21 0 0 1 .1 .3l-.3 .1zM189.3 234.8l.7-.1 .1 .4-.2 .1h-.5l-.1-.2zM189.3 237l.2-.1-.2 .3 .1 .3 .3-.1v-.2l.3 .3 .1-.3-.1-.2 .2 .2v.3l-.8 .1-.2-.2z"/>
<path d="M190.5 222.4h.6v1.5h-.6M190.5 223.9h.1M190.5 222.4h.1M190.8 234.2v-.5h-2.3v.8M190.8 234.2v.3M190.8 237.7v.3M191 222.4h.1M191.1 223.9h-.1M193.9 236.1v.9v-.4h-.7M205.8 235.1h.8M216.1 239.1l.1 .1M216.2 237.6l-.1 .1"/>
<path d="M216.7 237.6v.1M216.7 237.6h1.7v1.6h-1.7zM216.7 237.6h-.6v1.6h.6M216.7 239.1v.1M218.4 237.6h.6v1.6h-.6M218.4 239.1l.1 .1M218.5 237.6l-.1 .1M218.9 237.6l.1 .1M219 239.1l-.1 .1M224.7 229.6h.8M225 229.8h.3M225.8 226.3l3.5-3.4 1.5 1.6-3.3 3.4z"/>
<path d="M226.9 225.7l.2 .2 .2-.2 .7 .7-.2 .2 .2 .2M227.1 225.5l-.2 .2M227.7 225.6h.3l.2 .3-.1 .2h-.2l-.2-.2zM227.8 225.7l.2 .1 .1 .2h-.3zM228.1 225.3l.4 .3h-.1l-.2 .2zM228.1 220.3l.5-.5 1.3 1.4-.5 .4-.4-.4 .1-.2-.2-.3h-.4zM228.2 225.4l.1 .2-.1 .1zM228.3 225h.3a.26 .26 0 0 1 .2 .3 .26 .26 0 0 1-.2 .2l-.3-.3zM228.3 225l.4 .2v.2l-.4-.1zM228.5 224.2l-1.4 1.3 1.2 1.1M228.5 224.2l1.1 1.1M228.6 224.7h.3l.1 .4 .2-.1-.3 .3v-.6h-.2l-.1 .3z"/>
<path d="M228.6 223.9l.4-.3 1.1 1.2-.3 .3-.2-.2-.2 .2-.8-.7 .3-.2zM228.6 223.9l-.1 .3M229.8 225.1l-2 2-1.2-1.1 .3-.3M230.1 221l-.6 .7-.1-.1M230.3 220.9l-.2 .1M230.5 237.8v1M230.5 237.9h.3M232.5 224.7l.5-.4 1.3 1.3-.5 .5-.4-.5 .1-.2-.2-.3h-.4zM233.1 239.4v2.3h2.6v-2.3M233.1 224l-.6 .6 .1 .1M233.1 239.4v-1.1h2.6v1.1M233.1 239.4h2.6"/>
<path d="M233.1 239.3l.1 .1M233.2 223.9l1.8-1.8 1.5 1.4-1.8 1.9zM233.2 223.9l-.1 .1 1.5 1.5M233.2 238.3h-.1M234.6 225.5l-.6 .6-.1-.1M234.7 225.4l-.1 .1M235 222.1l.1-.1 1.5 1.4-.1 .1M235.4 221.8l.5-.4 .4 .4-.1 .2 .1 .3h.5l.4 .4-.5 .5zM235.6 238.3h.1M235.7 239.3l-.1 .1M235.8 221.4l-.7 .6M237.1 222.8h.1l-.6 .6"/>
<path d="M237.5 226.8h.3M237.5 226.8l.7 .6M237.7 239.4h2.6v2.3h-2.6zM237.7 239.3l.1 .1M237.7 239.4v-1.1h2.6v1.1M237.8 238.3h-.1M238.2 227.2v.2M238.3 226.1v.2M238.3 226.1l.6 .6M238.3 226.1l-.8 .7M238.3 226.3l.4 .4-.5 .5M238.3 226.3l-.5 .5 .4 .4"/>
<path d="M238.7 226.7h.2M238.9 226.7l-.7 .7M240.1 229.3h.2M240.2 238.3h.1M240.3 239.3l-.1 .1M240.7 229.7v.3M240.8 228.6v.2M240.8 228.6l.6 .6M240.8 228.6l-.7 .7M240.8 228.8l.4 .4-.5 .5M240.8 228.8l-.5 .5 .4 .4M241.2 229.2h.2"/>
<path d="M241.4 229.2l-.7 .8-.6-.7M242.6 231.9h.2M243.2 232.3l.1 .2M243.3 231.4l.5 .4-.6 .5M243.3 231.4l-.5 .5 .4 .4M243.3 231.1v.3M243.3 231.1l.7 .7M243.3 231.1l-.7 .8M243.8 231.8h.2M244 231.8l-.7 .7-.7-.6M245.2 234.4h.2M245.2 234.4l.6 .6"/>
<path d="M245.8 234.8v.2M245.9 233.9l.4 .4-.5 .5M245.9 233.9l-.5 .5 .4 .4M245.9 233.7v.2M245.9 233.7l.6 .6M245.9 233.7l-.7 .7M246.3 234.3h.2M246.5 234.3l-.7 .7M256.5 226.9l-3.5 3.6M149.3 245.7l5.8 5.8M154 241l-4.7 4.7M159.8 246.8l-4.7 4.7"/>
<path d="M161.2 248.2l-4.7 4.7-1.4-1.4M161.8 240.8l.6 .7M162.2 240.8l.2 .2M162.5 244.2l3.4-3.4 1.6 1.6-3.4 3.4zM162.5 240.1l-.7 .7h.4l.3-.2M162.7 240.8h.5l-.8 .7v-.5zM162.7 240.8l-.2-.2v-.5l.7 .7M163.2 243.9l.3-.3 .2 .2 .3-.2 .7 .7-.2 .3 .2 .1-.3 .4zM163.7 243.4l1.4-1.3 1.1 1.1-1.3 1.4zM163.7 243.4l-.2 .2M164.1 243.7l.3-.2v.4l.3 .1v-.2v.2h-.3v-.4zM164.5 243.2a.31 .31 0 0 1 .5 .1 .31 .31 0 0 1-.1 .5l-.4-.3z"/>
<path d="M164.6 243.3h.2l.2 .3h-.3zM164.8 243l.1 .1 .2-.2 .1 .6-.4-.3zM164.9 244.6l-.2 .1M165.1 242.1l.5-.5 1.1 1.1-.3 .3M165.1 243v.3l-.1-.1zM165.2 242.6a.33 .33 0 0 1 .4 .1 .33 .33 0 0 1 0 .4l-.4-.2zM165.2 242.7l.4 .1v.2l-.3-.1zM165.3 241.9l.2 .2-.2 .2 .7 .7 .2-.2 .2 .2M166.4 243l-.2 .2M168.6 240.6v.1M169 240.3h.1M169 240.3l-.4 .4 1.1 1.1 .4-.5"/>
<path d="M169.7 241.8h.1M182 242.7h3.7v3.8h-3.7zM182.5 240.7h.3M185.2 240.4h.3M188.7 249.4h1M188.7 249.7h.2v.3M192.3 241.4v.1M192.7 241.8h.1M193.4 240.3h.1M193.8 240.8l-.4-.5-1.1 1.1 1.6 1.6 1.1-1.1-1.2-1.2-1.1 1.1M194.3 243.4h.1M194.6 243.1a.42 .42 0 0 1 .4 .5 .42 .42 0 0 1-.6 .3 .42 .42 0 0 1-.2-.6"/>
<path d="M195 241.9l.5 .4-1.2 1.2-.4-.5M195.4 242.3v.1M197.1 243.5h.9M197.2 240.2h.8M197.2 242.7h.7M197.2 240.9h.7M204.2 243.5v.9M224.3 240.6h.9M224.7 249.6h.9M225 249.3h.2M227.6 242.2v.8M227.7 242.2v.8"/>
<path d="M233.1 241.7v1.1h2.6v-1.1M233.1 242.7l.1 .1M233.2 241.7l-.1 .1M233.8 249h.8M235.6 241.7l.1 .1M235.7 242.7l-.1 .1M237.7 242.7l.1 .1M237.7 241.7v1.2h2.6v-1.2M237.8 241.7l-.1 .1M240.2 241.7l.1 .1M240.3 242.7l-.1 .1"/>
<circle cx="64.7" cy="132.3" r=".63"/>
<circle cx="80.6" cy="139.7" r=".72"/>
<circle cx="85.3" cy="136.9" r=".63"/>
<circle cx="88.5" cy="129.7" r=".63"/>
<circle cx="93.9" cy="130.6" r=".72"/>
<circle cx="97.6" cy="136.4" r=".63"/>
<circle cx="113.3" cy="140" r=".63"/>
<circle cx="123.2" cy="137.7" r=".63"/>
<circle cx="123.7" cy="130.7" r=".72"/>
<circle cx="135.2" cy="138.2" r=".72"/>
<circle cx="145.1" cy="129.7" r=".72"/>
<circle cx="190.2" cy="138.1" r="6"/>
<circle cx="67.6" cy="153.7" r=".72"/>
<circle cx="71.8" cy="145.7" r=".72"/>
<circle cx="77.8" cy="154.2" r=".49"/>
<circle cx="77.9" cy="154.1" r=".6"/>
<circle cx="88.1" cy="156.3" r=".72"/>
<circle cx="91.9" cy="147.6" r=".72"/>
<circle cx="95" cy="152" r=".72"/>
<circle cx="98.8" cy="150.9" r=".72"/>
<circle cx="105.1" cy="150.4" r=".72"/>
<circle cx="108.2" cy="152.7" r=".72"/>
<circle cx="112.5" cy="158.5" r=".63"/>
<circle cx="115.3" cy="146.6" r=".72"/>
<circle cx="117.1" cy="141.3" r=".72"/>
<circle cx="123.1" cy="150.2" r=".63"/>
<circle cx="138.2" cy="143.9" r=".63"/>
<circle cx="143.3" cy="148.2" r=".63"/>
<circle cx="149.3" cy="158.4" r=".72"/>
<circle cx="150.7" cy="150.3" r=".72"/>
<circle cx="154.6" cy="153.3" r=".63"/>
<circle cx="175.1" cy="148" r=".72"/>
<circle cx="185.2" cy="155.7" r=".63"/>
<circle cx="37.5" cy="172.1" r="6"/>
<circle cx="52.6" cy="179.6" r=".63"/>
<circle cx="55" cy="171.2" r=".72"/>
<circle cx="87.5" cy="163.5" r=".72"/>
<circle cx="88.7" cy="176.7" r=".63"/>
<circle cx="96.4" cy="178.1" r=".63"/>
<circle cx="112" cy="178.2" r=".72"/>
<circle cx="112.3" cy="164" r=".72"/>
<circle cx="113.6" cy="174.2" r=".72"/>
<circle cx="115.1" cy="169.8" r=".63"/>
<circle cx="119.4" cy="176.2" r=".72"/>
<circle cx="125.3" cy="168.7" r=".63"/>
<circle cx="128.6" cy="170.9" r=".72"/>
<circle cx="130.5" cy="174.7" r=".63"/>
<circle cx="143" cy="163.8" r=".72"/>
<circle cx="155.8" cy="160.5" r=".63"/>
<circle cx="157.7" cy="170.4" r=".72"/>
<circle cx="161.8" cy="161.1" r=".72"/>
<circle cx="164.8" cy="175.6" r=".63"/>
<circle cx="59.5" cy="180.2" r=".63"/>
<circle cx="72.9" cy="180" r=".63"/>
<circle cx="142.8" cy="180.6" r=".72"/>
<circle cx="215.4" cy="218.1" r=".46"/>
<circle cx="234.9" cy="219.2" r=".43"/>
<circle cx="151.2" cy="223.1" r="4"/>
<circle cx="154.6" cy="234.8" r=".43"/>
<circle cx="159.2" cy="233.3" r=".43"/>
<circle cx="159.9" cy="238.2" r=".67"/>
<circle cx="169.2" cy="225" r=".67"/>
<circle cx="172.8" cy="225" r=".67"/>
<circle cx="174.2" cy="238" r=".43"/>
<circle cx="175" cy="233.2" r=".43"/>
<circle cx="176.6" cy="222.7" r=".43"/>
<circle cx="178.5" cy="236.6" r=".46"/>
<circle cx="180.9" cy="237.9" r=".46"/>
<circle cx="185.9" cy="226.9" r=".43"/>
<circle cx="193.7" cy="236.6" r=".46"/>
<circle cx="195.9" cy="222.8" r=".43"/>
<circle cx="196" cy="231.1" r=".43"/>
<circle cx="199.9" cy="225.3" r=".46"/>
<circle cx="201.1" cy="228.7" r=".46"/>
<circle cx="202.5" cy="224.3" r=".43"/>
<circle cx="203" cy="236.7" r=".43"/>
<circle cx="205.9" cy="232.8" r=".46"/>
<circle cx="206.2" cy="235.5" r=".46"/>
<circle cx="208" cy="231.3" r=".46"/>
<circle cx="209.8" cy="239.1" r=".43"/>
<circle cx="212.1" cy="231.6" r=".46"/>
<circle cx="213" cy="221.9" r=".43"/>
<circle cx="214.2" cy="239.1" r=".43"/>
<circle cx="214.7" cy="232.4" r=".46"/>
<circle cx="216.8" cy="229.4" r=".46"/>
<circle cx="219.3" cy="235.2" r=".46"/>
<circle cx="221.1" cy="222.3" r=".43"/>
<circle cx="224.3" cy="224.2" r=".46"/>
<circle cx="225.1" cy="229.4" r=".43"/>
<circle cx="230.1" cy="228.2" r=".46"/>
<circle cx="230.6" cy="238.3" r=".46"/>
<circle cx="233" cy="233.5" r=".46"/>
<circle cx="238.2" cy="226.8" r=".67"/>
<circle cx="240.8" cy="229.3" r=".67"/>
<circle cx="243.3" cy="231.8" r=".67"/>
<circle cx="245.8" cy="234.4" r=".67"/>
<circle cx="162.5" cy="240.8" r=".67"/>
<circle cx="168.2" cy="248.1" r=".43"/>
<circle cx="172.9" cy="244.6" r=".46"/>
<circle cx="182.8" cy="251.4" r=".46"/>
<circle cx="189.2" cy="249.6" r=".46"/>
<circle cx="191" cy="247.5" r=".43"/>
<circle cx="192.2" cy="245" r=".46"/>
<circle cx="197.6" cy="243.2" r=".46"/>
<circle cx="197.6" cy="240.5" r=".46"/>
<circle cx="198.5" cy="248.5" r=".46"/>
<circle cx="201.3" cy="244.3" r=".43"/>
<circle cx="202.3" cy="247.1" r=".46"/>
<circle cx="203.2" cy="240.4" r=".46"/>
<circle cx="203.4" cy="249.8" r=".46"/>
<circle cx="204.4" cy="243.9" r=".46"/>
<circle cx="204.9" cy="247.6" r=".46"/>
<circle cx="207.6" cy="247.5" r=".46"/>
<circle cx="209.7" cy="243.6" r=".43"/>
<circle cx="213.7" cy="249.7" r=".43"/>
<circle cx="214.3" cy="243.6" r=".43"/>
<circle cx="218.9" cy="248.8" r=".43"/>
<circle cx="219.7" cy="240" r=".46"/>
<circle cx="224.8" cy="240.9" r=".46"/>
<circle cx="225.1" cy="249.7" r=".43"/>
<circle cx="228" cy="242.6" r=".46"/>
<circle cx="229.4" cy="251" r=".43"/>
<circle cx="234.2" cy="249" r=".43"/>
<circle cx="238.3" cy="251.1" r=".43"/>
<circle cx="241.4" cy="245.2" r=".46"/>
<circle cx="243" cy="250.7" r=".43"/>
<circle cx="253" cy="245.7" r="4"/>
</g>
<g fill="#000">
<circle cx="139.1" cy="159.7" r=".25"/>
<circle cx="139.1" cy="161.9" r=".25"/>
<circle cx="139.1" cy="164" r=".25"/>
<circle cx="139.1" cy="166.2" r=".25"/>
</g>
<g fill="none" stroke="#000" stroke-width=".25">
<path d="M10.3 110.5h279.9v198.8h-279.9zM42.6 107v3.5M78.5 107v3.5M114.4 107v3.5M150.2 107v7.1M186.1 107v3.5M222 107v3.5M257.9 107v3.5M95.2 134.5h-22.1l-6.9 12M111.2 139.2h8.3l3.5 2.1M120.6 133.9h-10.5l-3 9.7M143.4 130.9h-11.2l-1.2 9.6"/>
<path d="M6.7 141.3h3.6M95.4 140.5h-6.4l-1.3 3.8M112.9 156.8h6.8l.7 3.3M165.2 152.9h-8.3l-7.4 4.4M290.2 141.3h3.6M6.7 175.6h3.6M77.9 174.8l-9.2 5.4h-10.9M114.7 177l-4.9 8.1h-8.3M139.2 174.8l3.5 1.3h11.2M146.6 168.6l-2.9 2.1h-8M290.2 175.6h3.6M85.4 183.5l-5.9 2.9h-9.6"/>
<path d="M124.3 182.6l-7 9.8h-22M135.6 182.8l-3 9.4h-10.5M6.7 209.9h7.2M286.6 209.9h7.2M154.6 239.8l-7 13.6h-2.5M156.3 231.8l-16 4.6h-15.9M160.3 220.5h6.7l2.7 5.3M165.7 237.2l6 15.6h8.4M202.3 229.5h-6.8l-2.8 2.5M210.7 222.1h-11.2l-6 .8M224.7 228.7l-3.3 3h-6.5M234.9 235.2h-11.2l-2.7 1.9"/>
<path d="M6.7 244.3h3.6M161 246.1l-13.4 7.3h-9.6M169.5 241.4l2.2 11.4h2.5M185.9 243.1l3.9 11h10.5M196.4 244.9l7.4 9.1h9.9M235.9 244.5l-4.5 3.9h-13M290.2 244.3h3.6M6.7 278.6h3.6M290.2 278.6h3.6M42.6 309.3v3.6M78.5 309.3v3.6M114.4 309.3v3.6"/>
<path d="M150.2 305.7v7.2M186.1 309.3v3.6M222 309.3v3.6M257.9 309.3v3.6"/>
</g>
<path d="M161 275.6h129.2v33.7h-129.2zM178.2 275.6v7.2M202.6 275.6v33.7M246.4 275.6v33.7M161 282.8h129.2M202.6 289.9h87.6M246.4 302.1h43.8M253.6 302.1v7.2M279.4 302.1v7.2" fill="none" stroke="#000" stroke-width=".34"/>
<g fill="#000" stroke="#000" stroke-width=".18">
<path d="M203.5 279.1h.9l.4 .3h-1v.9l.9 .1-.2 .2h-.7v1h-.3z" fill-rule="evenodd"/>
<path d="M204.2 279.4h.6l.1 .6-.2 .4-.9-.1h.5l.3-.1v-.5l-.2-.3z" fill-rule="evenodd"/>
<path d="M205 279.8h.2l.3 1.1 .1 .4-.2 .3z" fill-rule="evenodd"/>
<path d="M205.9 279.8h.2l-.5 2.1-.1 .2h-.3l.2-.2z" fill-rule="evenodd"/>
<path d="M206.3 279.8h.2v.3h.1l-.1 .3v1.2h-.2z" fill-rule="evenodd"/>
<path d="M206.6 279.9l.3-.1v.4l-.4-.1z" fill-rule="evenodd"/>
<path d="M207.3 279.9l.4-.1 .4 .3v1a.56 .56 0 0 1-.7 .6l-.2-.3 .6-.1 .1-.9-.3-.4h-.4z" fill-rule="evenodd"/>
<path d="M208.4 279.1h.2v.9h.3l-.3 .4v.7l.2 .3h-.2v.2h-.2z" fill-rule="evenodd"/>
<path d="M208.7 279.9l.3-.1 .3 .2 .2 .4v.7l-.2 .3-.3 .3h-.2l-.2-.2a.78 .78 0 0 0 .7-.6 .78 .78 0 0 0-.3-.8l-.4-.1z" fill-rule="evenodd"/>
<path d="M209.9 279.9l.5-.1 .3 .2 .1 1.6h-.2l-.1-.2h-.2l.1-.1 .1-.5-.7-.1 .7-.2-.1-.4-.6-.1z" fill-rule="evenodd"/>
<path d="M212.1 279.8h.2v.3h.2l-.2 .4v.5l.1 .3 .2 .1-.3 .1v.9h-.2z" fill-rule="evenodd"/>
<path d="M212.3 280h.3l-.3 .1z" fill-rule="evenodd"/>
<path d="M212.4 279.9l.4-.1 .3 .2 .1 .5-.1 .7a.49 .49 0 0 1-.5 .5l-.3-.2a.86 .86 0 0 0 .4-1.5h-.4z" fill-rule="evenodd"/>
<path d="M213.6 279.9l.4-.1 .3 .2h-.4a.95 .95 0 0 0-.1 1.4h-.3l-.1-.5v-.7z" fill-rule="evenodd"/>
<path d="M214.7 279.9a.49 .49 0 0 1 .5-.1 .49 .49 0 0 1 .3 .5h-.2l-.2-.3h-.5z" fill-rule="evenodd"/>
<path d="M216.5 279.1h.9l.3 .3h-1v.9l1 .1-.4 .2h-.6v1h-.2z" fill-rule="evenodd"/>
<path d="M217.2 279.4h.5l.1 .8-.1 .2-1-.1h.7l.2-.3a.38 .38 0 0 0-.4-.6z" fill-rule="evenodd"/>
<path d="M217.9 279.8h.3l.3 1.4-.1 .4z" fill-rule="evenodd"/>
<path d="M218.9 279.8h.2l-.5 2.1-.1 .2h-.4l.3-.2z" fill-rule="evenodd"/>
<path d="M219.2 279.8h.3v.3h.1l-.1 .4v1.1h-.3z" fill-rule="evenodd"/>
<path d="M219.5 279.9l.3-.1 .1 .1-.1 .3-.3-.1z" fill-rule="evenodd"/>
<path d="M220.2 279.9l.4-.1a1.06 1.06 0 0 1 .5 1.4l-.4 .5h-.3l-.3-.3h.5l.3-.3v-.9l-.3-.2h-.5z" fill-rule="evenodd"/>
<path d="M221.4 279.1h.2v.9h.3l-.3 .4v.7l.2 .3h-.2v.2h-.2z" fill-rule="evenodd"/>
<path d="M221.6 280l.3-.2h.2l.3 .5-.1 1.1-.3 .3-.4-.2 .3-.1a.93 .93 0 0 0 .1-1.4z" fill-rule="evenodd"/>
<path d="M222.8 280l.5-.2 .4 .3 .1 1.5h-.2l-.1-.2h-.3l.2-.2 .1-.4-.7-.1 .6-.2 .1-.3-.2-.2h-.5z" fill-rule="evenodd"/>
<path d="M225.1 279.8h.2v.3h.2l-.2 .3v.5l.1 .4 .2 .1-.3 .1v.9h-.2z" fill-rule="evenodd"/>
<path d="M225.3 280h.3l-.3 .1z" fill-rule="evenodd"/>
<path d="M225.3 280l.4-.2 .3 .2 .1 .5-.1 .8a.41 .41 0 0 1-.3 .4 .41 .41 0 0 1-.4-.2 .7 .7 0 0 0 .6-.4 .7 .7 0 0 0 0-.7l-.2-.4z" fill-rule="evenodd"/>
<path d="M226.6 279.9l.4-.1 .3 .2h-.4l-.3 .3v.8l.2 .3h-.3l-.1-.3v-.7z" fill-rule="evenodd"/>
<path d="M227.7 279.9a.47 .47 0 0 1 .5-.1 .47 .47 0 0 1 .3 .5h-.2l-.2-.3h-.5z" fill-rule="evenodd"/>
<path d="M203.6 293.8l1.3 .1 .4 .4h-1.4v1.3h1.3l-.4 .4h-.9v1.4h-.3z" fill-rule="evenodd"/>
<path d="M205.1 282.1h.4l-.3 .3h-.1z" fill-rule="evenodd"/>
<path d="M204.6 294.3h.7l.1 .7-.2 .6h-1.3h.7a.49 .49 0 0 0 .5-.5l-.2-.7z" fill-rule="evenodd"/>
<path d="M205.7 298l.6 .1-.1 .3-.3 .1h-.2z" fill-rule="evenodd"/>
<path d="M205.6 294.9h.3l.3 1.4 .2 .6-.2 .5z" fill-rule="evenodd"/>
<path d="M206.8 294.9h.3l-.8 3.2h-.4l.2-.2z" fill-rule="evenodd"/>
<path d="M207.1 280.1l.5-.1-.3 .2-.1 .3 .1 .7 .3 .2-.5-.1z" fill-rule="evenodd"/>
<path d="M207.3 294.9h.3v.3h.3l-.3 .5v1.7h-.3z" fill-rule="evenodd"/>
<path d="M207.7 294.9a.31 .31 0 0 1 .3-.1 .31 .31 0 0 1 .3 .1l-.1 .4-.6-.1z" fill-rule="evenodd"/>
<path d="M208.6 294.2h.5l-.2 .1-.2 .8v1.5l.2 .4 .2 .1-.5 .1-.2-.7v-1.4z" fill-rule="evenodd"/>
<path d="M208.6 281.4h.3z" fill-rule="evenodd"/>
<path d="M208.7 294l.2-.1a.52 .52 0 0 1 .8 .4l.2 1-.1 1.6-.3 .5-.6 .1-.3-.3 .6-.1 .3-.3 .1-1.7-.2-.7-.2-.2h-.6z" fill-rule="evenodd"/>
<path d="M209.8 280.1l.4-.1-.2 .1-.1 .3-.2-.1z" fill-rule="evenodd"/>
<path d="M209.8 280.8h.7h-.1a.37 .37 0 0 0-.5 .2 .37 .37 0 0 0 .1 .4l.5 .1a.45 .45 0 0 1-.4 .2 .45 .45 0 0 1-.4-.3z" fill-rule="evenodd"/>
<path d="M210.1 295.9h.9v.5h-.9z" fill-rule="evenodd"/>
<path d="M210.1 281.4h.4z" fill-rule="evenodd"/>
<path d="M211 279.1h.2v2.5h-.2z" fill-rule="evenodd"/>
<path d="M211.6 279.1h.2v2.5h-.2z" fill-rule="evenodd"/>
<path d="M211.4 293.8l1.2 .1 .4 .4h-1.3v1.3h1.3l-.4 .4h-.9v1.4h-.3z" fill-rule="evenodd"/>
<path d="M212.4 294.3h.7v.8l-.1 .5h-1.3h.6l.4-.2 .1-.8z" fill-rule="evenodd"/>
<path d="M213.5 294.9h.3v2.5h-.3z" fill-rule="evenodd"/>
<path d="M213.5 293.8h.3v.5h-.3z" fill-rule="evenodd"/>
<path d="M213.5 281.4h.5l.2-.4h.3l-.2 .5-.2 .2h-.3z" fill-rule="evenodd"/>
<path d="M214.3 295.1h.6l-.3 .2-.2 .6h1.3v.3h-1.3l.2 .7 .3 .2h-.6l-.1-.3-.1-1z" fill-rule="evenodd"/>
<path d="M214 280h.3l.1 .4h-.2z" fill-rule="evenodd"/>
<path d="M214.6 280h.5l-.3 .1v.3l.7 .4 .1 .5-.2 .3-.5 .1-.3-.3h.6a.39 .39 0 0 0 .1-.4 .39 .39 0 0 0-.5-.2l-.2-.3z" fill-rule="evenodd"/>
<path d="M214.5 281.1h.3l.2 .3h-.4z" fill-rule="evenodd"/>
<path d="M214.6 294.9h.6l.3 .3 .2 .7h-1.3h1l-.3-.7-.8-.1z" fill-rule="evenodd"/>
<path d="M214.3 297.1h.8l.3-.5 .3 .1-.1 .1a.76 .76 0 0 1-.9 .7z" fill-rule="evenodd"/>
<path d="M217 295.2l.3-.1-1.1 2-.3 .3v-.3z" fill-rule="evenodd"/>
<path d="M215.9 294.9h1.4v.2l-1.4 .1z" fill-rule="evenodd"/>
<path d="M215.9 297.4l.4-.3h1.1v.3z" fill-rule="evenodd"/>
<path d="M217.7 295.2l.7-.1-.3 .2-.3 .5 .1 1 .4 .3h-.5l-.2-.3v-1z" fill-rule="evenodd"/>
<path d="M218 282.1l.5 .1-.3 .2h-.1z" fill-rule="evenodd"/>
<path d="M217.9 294.9a.75 .75 0 0 1 .8 0 .75 .75 0 0 1 .4 .7v.9l-.2 .6-.4 .4-.4-.1-.3-.3h.8l.2-.6v-.7l-.1-.4-.3-.3h-.6z" fill-rule="evenodd"/>
<path d="M219.3 295.9h.9v.5h-.9z" fill-rule="evenodd"/>
<path d="M220.1 280.1l.5-.1-.1 .1a.99 .99 0 0 0-.2 1.1l.2 .2h-.4l-.1-.2v-.7z" fill-rule="evenodd"/>
<path d="M220.5 296.3l.3-.1 .1 .6 .5 .3h-.7z" fill-rule="evenodd"/>
<path d="M220.8 294a.82 .82 0 0 1 1.3 .2h-.9a.61 .61 0 0 0-.3 .8 .61 .61 0 0 0 .7 .4 1.1 1.1 0 0 1 .5 1.8l-.3 .2-.6 .1-.5-.4h.7a.64 .64 0 0 0 .6-.7 .64 .64 0 0 0-.6-.6l-.5-.2a1.05 1.05 0 0 1-.3-1.1z" fill-rule="evenodd"/>
<path d="M221.6 281.4h.3z" fill-rule="evenodd"/>
<path d="M221.6 294.2h.5l.1 .7h-.2l-.2-.5z" fill-rule="evenodd"/>
<path d="M222.7 280.1l.5-.1-.3 .2v.2l-.2-.1z" fill-rule="evenodd"/>
<path d="M222.7 280.8h.8h-.1a.38 .38 0 0 0-.5 .2 .38 .38 0 0 0 .1 .4l.5 .1-.1 .1a.46 .46 0 0 1-.8-.3z" fill-rule="evenodd"/>
<path d="M222.8 294.2l.3-.3v1h.3v.3h-.3v1.7l.1 .2h-.4v-1.9h-.3v-.3h.3z" fill-rule="evenodd"/>
<path d="M223.1 281.4h.4z" fill-rule="evenodd"/>
<path d="M222.8 297.1h.6l-.1 .3a.38 .38 0 0 1-.5-.3z" fill-rule="evenodd"/>
<path d="M223.6 295.2l.7-.1a.44 .44 0 0 0-.4 .6l-.3-.1z" fill-rule="evenodd"/>
<path d="M223.7 296.2l1-.1-.6 .2a.43 .43 0 0 0-.3 .5 .43 .43 0 0 0 .4 .3l.5 .1a.62 .62 0 0 1-.7 .3 .62 .62 0 0 1-.5-.5z" fill-rule="evenodd"/>
<path d="M224 279.1h.2v2.5h-.2z" fill-rule="evenodd"/>
<path d="M223.8 294.9a.69 .69 0 0 1 1.2 .4v2.1h-.3v-.3h-.3l.3-.4v-.6h-.9l.9-.3v-.4l-.3-.3h-.7z" fill-rule="evenodd"/>
<path d="M224.2 297.1h.5z" fill-rule="evenodd"/>
<path d="M224.5 279.1h.2v2.5h-.2z" fill-rule="evenodd"/>
<path d="M225.4 294.9h.3v.3h.3l-.3 .4v1.8h-.3z" fill-rule="evenodd"/>
<path d="M225.7 295.1h.4l-.1 .1h-.3z" fill-rule="evenodd"/>
<path d="M225.9 294.9l.4-.1 .4 .3 .1 2.3h-.3v-2l-.2-.2-.6-.1z" fill-rule="evenodd"/>
<path d="M226.5 281.4h.5l.2-.4h.2l-.1 .5-.3 .2h-.3z" fill-rule="evenodd"/>
<path d="M226.9 280h.4l.1 .4h-.2z" fill-rule="evenodd"/>
<path d="M227.6 280.1l.4-.1-.2 .1a.51 .51 0 0 0 .5 .6l.2 .2-.1 .6-.2 .2-.5-.1-.1-.2h.5l.2-.1v-.3l-.7-.3z" fill-rule="evenodd"/>
<path d="M227.5 281.1h.2l.2 .3h-.3z" fill-rule="evenodd"/>
<path d="M227.4 295l.5-.2 .4 .3-.6 .1-.2 .2-.1 1.1 .2 .5 .2 .1h-.5l-.1-.4-.1-.9z" fill-rule="evenodd"/>
<path d="M227.3 297.1h1a.42 .42 0 0 1-.6 .3z" fill-rule="evenodd"/>
<path d="M228.3 293.8h.3v3.6h-.3v-.3h-.3l.3-.5v-.9l-.1-.3-.3-.3h.4z" fill-rule="evenodd"/>
<path d="M229.1 295.2l.6-.1a.39 .39 0 0 0-.4 .6l-.3-.1z" fill-rule="evenodd"/>
<path d="M229.2 296.1h.9l-.6 .2a.43 .43 0 0 0-.3 .5 .43 .43 0 0 0 .4 .3l.5 .1a.62 .62 0 0 1-.7 .3 .62 .62 0 0 1-.5-.5v-.5z" fill-rule="evenodd"/>
<path d="M229.2 294.9a.69 .69 0 0 1 1.2 .4l.1 2.1h-.3l-.1-.3h-.3l.3-.4v-.6h-.9l.5-.2a.27 .27 0 0 0 .3-.1 .27 .27 0 0 0 .1-.2l-.1-.3-.2-.2h-.7z" fill-rule="evenodd"/>
<path d="M229.6 297.1h.5z" fill-rule="evenodd"/>
<path d="M230.8 293.8h.3v3.6h-.3z" fill-rule="evenodd"/>
<path d="M231.6 295.1h.6h-.1a1.51 1.51 0 0 0 .1 2h-.5l-.2-.4v-1.1z" fill-rule="evenodd"/>
<path d="M231.7 295.1a.64 .64 0 0 1 .6-.3 .64 .64 0 0 1 .5 .4l.2 .7-.1 1.1-.4 .4-.5 .1-.3-.4h.8l.2-.5v-.7l-.3-.7-.8-.1z" fill-rule="evenodd"/>
<path d="M233.4 294.9h.2v.3h.3l-.3 .6v1.6h-.2z" fill-rule="evenodd"/>
<path d="M233.7 295.1h.4l-.2 .1h-.3z" fill-rule="evenodd"/>
<path d="M233.8 295l.4-.2a.63 .63 0 0 1 .5 .6v2h-.3v-2l-.2-.2-.5-.1z" fill-rule="evenodd"/>
<path d="M235.3 295.1h.6a.69 .69 0 0 0-.5 .8h1.2v.3h-1.2l.1 .7 .4 .2h-.6l-.1-.1-.1-1.2z" fill-rule="evenodd"/>
<path d="M235.5 294.9a.62 .62 0 0 1 .9 .3l.2 .7h-1.2h.9l-.2-.7-.8-.1z" fill-rule="evenodd"/>
<path d="M235.3 297.1h.7l.2-.1 .1-.4 .3 .1a.74 .74 0 0 1-1.1 .7z" fill-rule="evenodd"/>
<path d="M236.7 298.1h1.9v.4h-1.9z" fill-rule="evenodd"/>
<path d="M238.9 294.1l.3-.2 .4-.1 .5 .4h-.6a.56 .56 0 0 0-.5 .7h-.3z" fill-rule="evenodd"/>
<path d="M239.5 294.2h.6l.1 .8-.3 .7-.8 1.3h1.1v.4h-1.5a5.3 5.3 0 0 1 1.1-2.1l.1-.2a.73 .73 0 0 0-.3-.9z" fill-rule="evenodd"/>
<path d="M240.7 296.9h.3v.5h-.3z" fill-rule="evenodd"/>
<path d="M241.6 294.2h.6l-.3 .1-.2 .7 .1 1.6 .1 .4 .3 .1-.5 .1-.2-.6-.1-1.6z" fill-rule="evenodd"/>
<path d="M241.7 294l.3-.2 .4 .1 .2 .1 .3 .9v1a1.84 1.84 0 0 1-.5 1.6h-.4l-.3-.3 .5-.1 .3-.3 .2-.8-.1-1.4-.3-.4h-.7z" fill-rule="evenodd"/>
<path d="M243.4 296.9h.3v.5h-.3z" fill-rule="evenodd"/>
<path d="M244.3 294.7l.2-.1h.4l-.6 .5z" fill-rule="evenodd"/>
<path d="M245 293.8h.2v3.6h-.3v-2.8h-.4z" fill-rule="evenodd"/>
</g>
<g fill="#000">
<path d="M65.9 146.3l.7 .4-1.6 2zM87.2 144.1l.9 .3-1.3 2.2zM106.7 143.4l.8 .3-1.2 2.2zM123.2 140.9l1.9 1.7-2.3-1zM130.6 140.5l.8 .1-.8 2.4zM147.4 158.5l1.9-1.6 .4 .7zM77.7 174.5l2.4-1-2 1.7zM116 174.9l-1 2.3-.7-.4zM119.9 160.2l.9-.1 .1 2.5zM136.9 173.9l2.5 .5-.3 .7zM146.3 168.3l2.2-1.2-1.7 1.9zM85.2 183.1l2.5-.7-2.1 1.5z"/>
<path d="M125.7 180.5l-1.1 2.3-.6-.5zM136.3 180.4l-.3 2.6-.8-.3zM155.8 237.5l-.8 2.4-.7-.3zM156.2 231.4l2.5-.3-2.3 1.1zM164.8 234.8l1.3 2.2-.7 .3zM169.3 225.9l.8-.3 .8 2.4zM192.4 231.7l.6 .6-2.2 1.4zM191.1 223.3l2.4-.8 .1 .8zM219 238.5l1.8-1.8 .5 .7zM224.5 228.4l2.1-1.4-1.6 2zM160.8 245.8l2.4-.9-2 1.6zM169 239l.9 2.3-.8 .2z"/>
<path d="M185.1 240.7l1.2 2.2-.8 .3zM194.8 243l1.9 1.6-.7 .6zM235.6 244.2l2.1-1.4-1.6 2z"/>
</g>
<use href="#words"/>
</svg>
